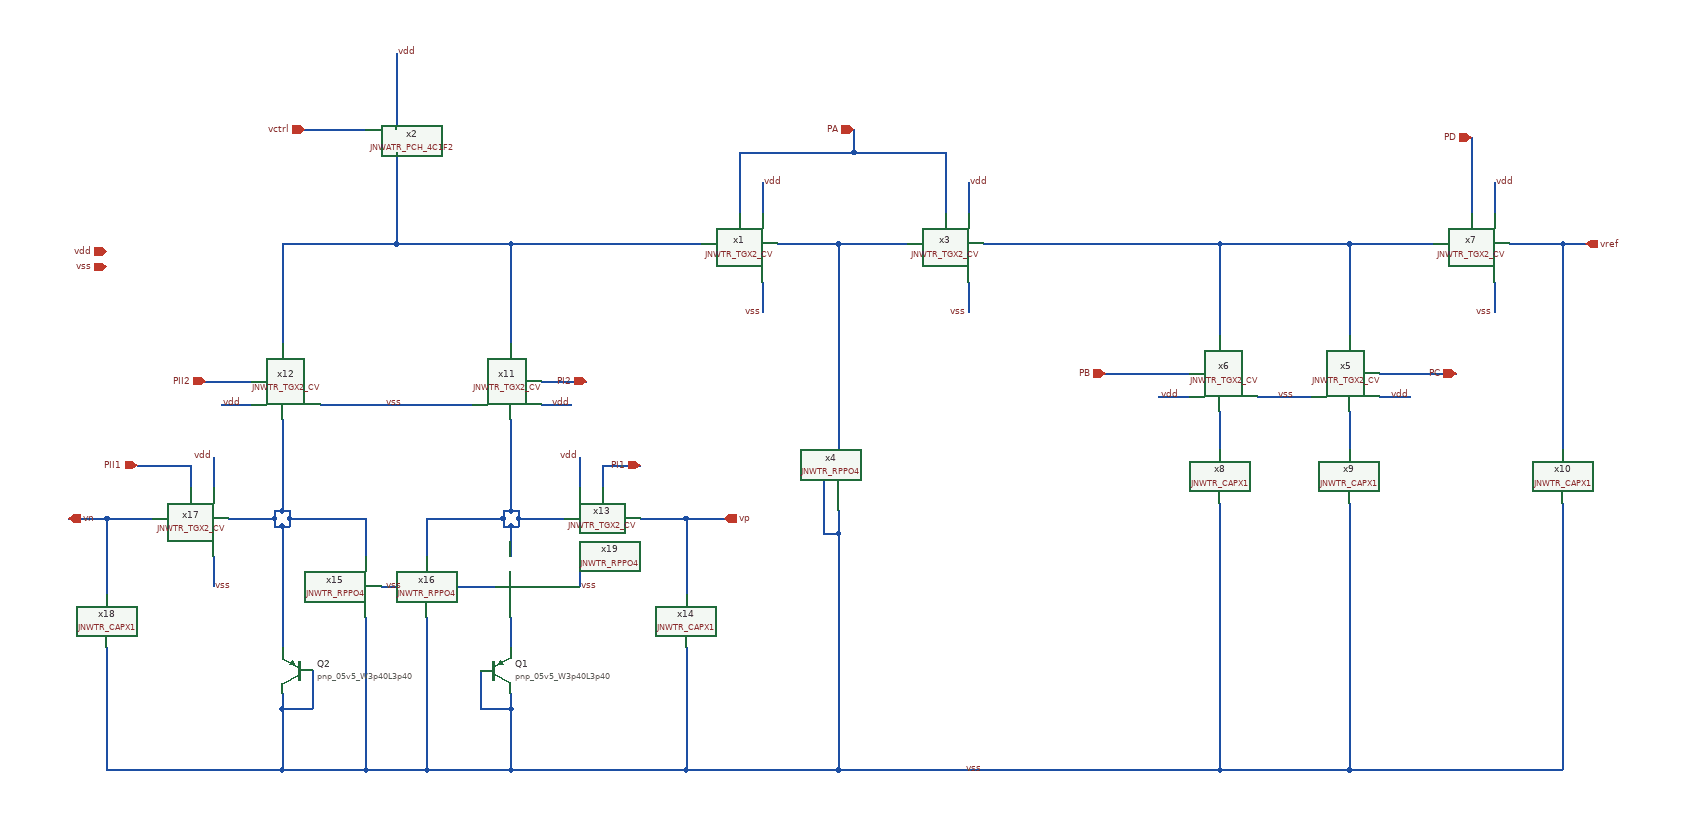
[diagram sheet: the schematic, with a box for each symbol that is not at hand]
v {xschem version=3.4.5 file_version=1.2
}
G {}
K {}
V {}
S {}
E {}
N 1610 -810 1700 -810 {
lab=#net1}
N 1530 -810 1610 -810 {
lab=#net1}
N 1610 -810 1610 -540 {
lab=#net1}
N 1590 -500 1590 -430 {
lab=vss}
N 1590 -430 1610 -430 {
lab=vss}
N 1610 -460 1610 -430 {
lab=vss}
N 1800 -810 2110 -810 {
lab=#net2}
N 1510 -760 1510 -720 {
lab=vss}
N 1510 -890 1510 -850 {
lab=vdd}
N 1480 -930 1480 -850 {
lab=PA}
N 1780 -760 1780 -720 {
lab=vss}
N 1780 -890 1780 -850 {
lab=vdd}
N 1750 -930 1750 -850 {
lab=PA}
N 2160 -610 2230 -610 {
lab=vss}
N 2030 -610 2070 -610 {
lab=vdd}
N 2110 -810 2110 -690 {
lab=#net2}
N 2280 -810 2280 -690 {
lab=#net2}
N 1960 -640 2070 -640 {
lab=PB}
N 2320 -640 2420 -640 {
lab=PC}
N 2320 -610 2360 -610 {
lab=vdd}
N 2280 -810 2390 -810 {
lab=#net2}
N 2110 -810 2280 -810 {
lab=#net2}
N 2470 -760 2470 -720 {
lab=vss}
N 2470 -890 2470 -850 {
lab=vdd}
N 2440 -950 2440 -850 {
lab=PD}
N 2490 -810 2560 -810 {
lab=vref}
N 2560 -810 2560 -540 {
lab=vref}
N 2280 -590 2280 -540 {
lab=#net3}
N 2110 -590 2110 -540 {
lab=#net4}
N 800 -600 840 -600 {
lab=vdd}
N 1220 -630 1280 -630 {
lab=PI2}
N 1220 -600 1260 -600 {
lab=vdd}
N 880 -810 880 -680 {
lab=#net5}
N 1180 -810 1430 -810 {
lab=#net5}
N 880 -810 1030 -810 {
lab=#net5}
N 1180 -810 1180 -680 {
lab=#net5}
N 1030 -810 1180 -810 {
lab=#net5}
N 930 -600 1130 -600 {
lab=vss}
N 1180 -460 1190 -460 {
lab=#net6}
N 1190 -450 1190 -440 {
lab=#net6}
N 1170 -450 1170 -440 {
lab=#net6}
N 1170 -460 1180 -460 {
lab=#net6}
N 880 -460 890 -460 {
lab=#net6}
N 890 -450 890 -440 {
lab=#net6}
N 880 -440 890 -440 {
lab=#net6}
N 870 -450 870 -440 {
lab=#net6}
N 870 -460 880 -460 {
lab=#net6}
N 1190 -450 1250 -450 {
lab=#net6}
N 1190 -460 1190 -450 {
lab=#net6}
N 1180 -580 1180 -460 {
lab=#net6}
N 880 -580 880 -460 {
lab=#net6}
N 1410 -450 1460 -450 {
lab=vp}
N 1410 -450 1410 -350 {
lab=vp}
N 1350 -450 1410 -450 {
lab=vp}
N 1610 -430 1610 -120 {
lab=vss}
N 890 -460 890 -450 {
lab=#net6}
N 1170 -460 1170 -450 {
lab=#net6}
N 1070 -450 1170 -450 {
lab=#net6}
N 870 -440 880 -440 {
lab=#net6}
N 1180 -440 1190 -440 {
lab=#net6}
N 880 -440 880 -280 {
lab=#net6}
N 890 -450 990 -450 {
lab=#net6}
N 810 -450 870 -450 {
lab=#net6}
N 600 -450 650 -450 {
lab=vp}
N 650 -450 650 -350 {
lab=vp}
N 650 -450 710 -450 {
lab=vp}
N 870 -460 870 -450 {
lab=#net6}
N 780 -630 840 -630 {
lab=PII2}
N 650 -280 650 -120 {
lab=vss}
N 2280 -120 2560 -120 {
lab=vss}
N 2560 -470 2560 -120 {
lab=vss}
N 2280 -470 2280 -120 {
lab=vss}
N 2110 -120 2280 -120 {
lab=vss}
N 2110 -470 2110 -120 {
lab=vss}
N 1610 -120 2110 -120 {
lab=vss}
N 1410 -280 1410 -120 {
lab=vss}
N 1180 -120 1410 -120 {
lab=vss}
N 1410 -120 1610 -120 {
lab=vss}
N 1180 -200 1180 -120 {
lab=vss}
N 1070 -120 1180 -120 {
lab=vss}
N 880 -200 880 -120 {
lab=vss}
N 650 -120 880 -120 {
lab=vss}
N 920 -250 920 -200 {
lab=vss}
N 880 -200 920 -200 {
lab=vss}
N 880 -220 880 -200 {
lab=vss}
N 1140 -250 1140 -200 {
lab=vss}
N 1140 -200 1180 -200 {
lab=vss}
N 1180 -220 1180 -200 {
lab=vss}
N 1270 -400 1270 -360 {
lab=vss}
N 790 -400 790 -360 {
lab=vss}
N 1270 -530 1270 -490 {
lab=vdd}
N 790 -530 790 -490 {
lab=vdd}
N 1030 -930 1030 -810 {
lab=#net5}
N 910 -960 990 -960 {
lab=vctrl}
N 1030 -1060 1030 -960 {
lab=vdd}
N 990 -450 990 -400 {
lab=#net6}
N 1070 -450 1070 -400 {
lab=#net6}
N 880 -120 990 -120 {
lab=vss}
N 1070 -320 1070 -120 {
lab=vss}
N 990 -120 1070 -120 {
lab=vss}
N 1010 -360 1160 -360 {
lab=vss}
N 990 -320 990 -120 {
lab=vss}
N 1180 -440 1180 -400 {
lab=#net6}
N 1170 -440 1180 -440 {
lab=#net6}
N 1180 -320 1180 -280 {
lab=#net7}
N 760 -520 760 -490 {
lab=PII1}
N 690 -520 760 -520 {
lab=PII1}
N 1300 -520 1300 -490 {
lab=PI1}
N 1300 -520 1350 -520 {
lab=PI1}
N 2560 -810 2590 -810 {
lab=vref}
N 1630 -930 1750 -930 {
lab=PA}
N 1630 -960 1630 -930 {
lab=PA}
N 1480 -930 1630 -930 {
lab=PA}
C {devices/ipin.sym} 650 -800 0 0 {name=p1 lab=vdd}
C {devices/ipin.sym} 650 -780 0 0 {name=p2 lab=vss
}
C {JNW_TR_SKY130A/JNWTR_TGX2_CV.sym} 1420 -810 0 0 {name=x1 }
C {JNW_TR_SKY130A/JNWTR_RPPO4.sym} 1610 -540 1 0 {name=x4 }
C {devices/lab_wire.sym} 1800 -120 0 0 {name=p4 sig_type=std_logic lab=vss
}
C {devices/lab_wire.sym} 1510 -720 0 0 {name=p5 sig_type=std_logic lab=vss
}
C {devices/lab_wire.sym} 1510 -890 0 1 {name=p6 sig_type=std_logic lab=vdd

}
C {JNW_TR_SKY130A/JNWTR_TGX2_CV.sym} 1690 -810 0 0 {name=x3 }
C {devices/lab_wire.sym} 2210 -610 0 0 {name=p7 sig_type=std_logic lab=vss
}
C {JNW_TR_SKY130A/JNWTR_TGX2_CV.sym} 2280 -700 1 0 {name=x5 }
C {JNW_TR_SKY130A/JNWTR_TGX2_CV.sym} 2110 -700 3 1 {name=x6 }
C {devices/lab_wire.sym} 1780 -720 0 0 {name=p9 sig_type=std_logic lab=vss
}
C {devices/lab_wire.sym} 1780 -890 0 1 {name=p11 sig_type=std_logic lab=vdd

}
C {devices/lab_wire.sym} 2030 -610 0 1 {name=p12 sig_type=std_logic lab=vdd

}
C {devices/lab_wire.sym} 2360 -610 0 0 {name=p13 sig_type=std_logic lab=vdd

}
C {JNW_TR_SKY130A/JNWTR_TGX2_CV.sym} 2380 -810 0 0 {name=x7 }
C {devices/lab_wire.sym} 2470 -720 0 0 {name=p14 sig_type=std_logic lab=vss
}
C {devices/lab_wire.sym} 2470 -890 0 1 {name=p17 sig_type=std_logic lab=vdd

}
C {JNW_TR_SKY130A/JNWTR_CAPX1.sym} 2110 -480 0 0 {name=x8 }
C {JNW_TR_SKY130A/JNWTR_CAPX1.sym} 2280 -480 0 0 {name=x9 }
C {JNW_TR_SKY130A/JNWTR_CAPX1.sym} 2560 -480 0 0 {name=x10 }
C {devices/lab_wire.sym} 1040 -600 0 0 {name=p18 sig_type=std_logic lab=vss
}
C {JNW_TR_SKY130A/JNWTR_TGX2_CV.sym} 1180 -690 1 0 {name=x11 }
C {JNW_TR_SKY130A/JNWTR_TGX2_CV.sym} 880 -690 3 1 {name=x12 }
C {devices/lab_wire.sym} 800 -600 0 1 {name=p19 sig_type=std_logic lab=vdd

}
C {devices/lab_wire.sym} 1260 -600 0 0 {name=p20 sig_type=std_logic lab=vdd

}
C {JNW_TR_SKY130A/JNWTR_TGX2_CV.sym} 1360 -450 0 1 {name=x13 }
C {JNW_TR_SKY130A/JNWTR_CAPX1.sym} 1410 -290 0 0 {name=x14 }
C {JNW_TR_SKY130A/JNWTR_RPPO4.sym} 990 -400 3 1 {name=x15 }
C {JNW_TR_SKY130A/JNWTR_RPPO4.sym} 1070 -400 1 0 {name=x16 }
C {JNW_TR_SKY130A/JNWTR_TGX2_CV.sym} 700 -450 0 0 {name=x17 }
C {JNW_TR_SKY130A/JNWTR_CAPX1.sym} 650 -290 0 1 {name=x18 }
C {sky130_fd_pr/pnp_05v5.sym} 1160 -250 0 0 {name=Q1
model=pnp_05v5_W3p40L3p40
m=8
spiceprefix=X
}
C {sky130_fd_pr/pnp_05v5.sym} 900 -250 0 1 {name=Q2
model=pnp_05v5_W3p40L3p40
m=1
spiceprefix=X
}
C {devices/lab_wire.sym} 1270 -360 0 1 {name=p23 sig_type=std_logic lab=vss
}
C {devices/lab_wire.sym} 790 -360 0 1 {name=p24 sig_type=std_logic lab=vss
}
C {devices/lab_wire.sym} 1270 -530 0 0 {name=p25 sig_type=std_logic lab=vdd

}
C {devices/lab_wire.sym} 790 -530 0 0 {name=p26 sig_type=std_logic lab=vdd

}
C {devices/ipin.sym} 910 -960 0 0 {name=p27 lab=vctrl}
C {devices/lab_wire.sym} 1030 -1060 0 1 {name=p28 sig_type=std_logic lab=vdd

}
C {devices/lab_wire.sym} 1040 -360 0 0 {name=p29 sig_type=std_logic lab=vss
}
C {JNW_TR_SKY130A/JNWTR_RPPO4.sym} 1180 -400 1 0 {name=x19 }
C {JNW_ATR_SKY130A/JNWATR_PCH_4C1F2.sym} 990 -960 0 0 {name=x2 }
C {devices/ipin.sym} 2440 -950 1 0 {name=p8 lab=PD}
C {devices/ipin.sym} 1960 -640 0 0 {name=p10 lab=PB}
C {devices/ipin.sym} 2420 -640 2 0 {name=p15 lab=PC}
C {devices/ipin.sym} 1630 -960 1 0 {name=p16 lab=PA}
C {devices/ipin.sym} 1280 -630 2 0 {name=p31 lab=PI2}
C {devices/ipin.sym} 780 -630 0 0 {name=p32 lab=PII2}
C {devices/ipin.sym} 690 -520 0 0 {name=p33 lab=PII1}
C {devices/ipin.sym} 1350 -520 2 0 {name=p34 lab=PI1}
C {devices/opin.sym} 2590 -810 0 0 {name=p3 lab=vref}
C {devices/opin.sym} 1460 -450 0 0 {name=p21 lab=vp}
C {devices/opin.sym} 600 -450 2 0 {name=p22 lab=vn}
